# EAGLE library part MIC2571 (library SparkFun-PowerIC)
Single Cell Switching Regulator - MIC2571

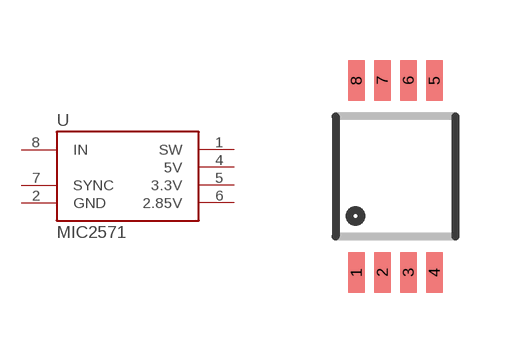
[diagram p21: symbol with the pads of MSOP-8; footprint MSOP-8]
Designator prefix U

## MIC2571SMD  [MSOP-8]
1  SW
2  GND
4  5V
5  3.3V
6  2.85V
7  SYNC
8  IN

## Footprint MSOP-8 (pad centres in mm)
smd 0.41 x 1.02: 1 -0.975,-2.4; 2 -0.325,-2.4; 3 0.325,-2.4; 4 0.975,-2.4; 5 0.975,2.4; 6 0.325,2.4; 7 -0.325,2.4; 8 -0.975,2.4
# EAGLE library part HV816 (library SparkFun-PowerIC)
High-drive dimmable EL inverter Supertex, available in SOW16 and QFN16

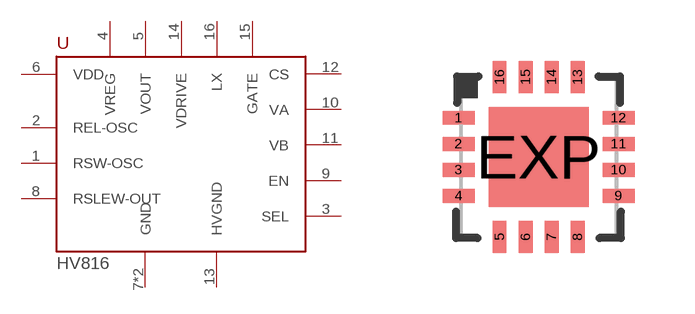
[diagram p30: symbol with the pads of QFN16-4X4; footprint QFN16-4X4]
Designator prefix -

## HV816K6  [QFN16-4X4]
1  RSW-OSC
2  REL-OSC
3  SEL
4  VREG
5  VOUT
6  VDD
7  GND
8  RSLEW-OUT
9  EN
10  VA
11  VB
12  CS
13  HVGND
14  VDRIVE
15  GATE
16  LX
EXP  GND

## Footprint QFN16-4X4 (pad centres in mm)
16-Lead Plastic Quad Flat, No Lead Package (ML) - 4x4x0.9mm Body [QFN] Source: http://ww1.microchip.com/downloads/en/DeviceDoc/41203E.pdf
smd 0.8 x 0.35: 1 -2,0.975; 2 -2,0.325; 3 -2,-0.325; 4 -2,-0.975; 9 2,-0.975; 10 2,-0.325; 11 2,0.325; 12 2,0.975
smd 0.35 x 0.8: 5 -0.975,-2; 6 -0.325,-2; 7 0.325,-2; 8 0.975,-2; 13 0.975,2; 14 0.325,2; 15 -0.325,2; 16 -0.975,2
smd 2.5 x 2.5: EXP 0,0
